One B-rep face of a CAD part: STEP entity #565.
In plain terms, the planar face has unit normal (0, -1, 0).
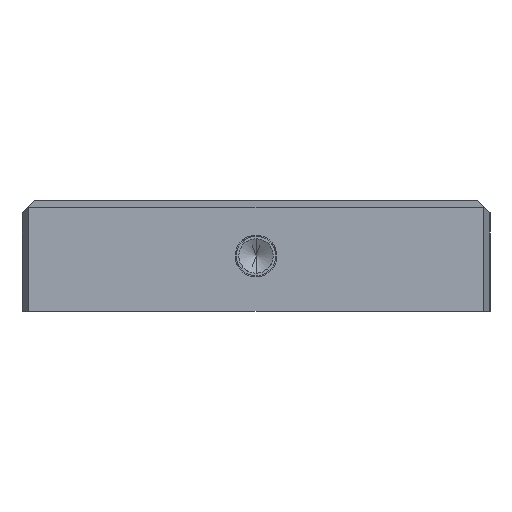
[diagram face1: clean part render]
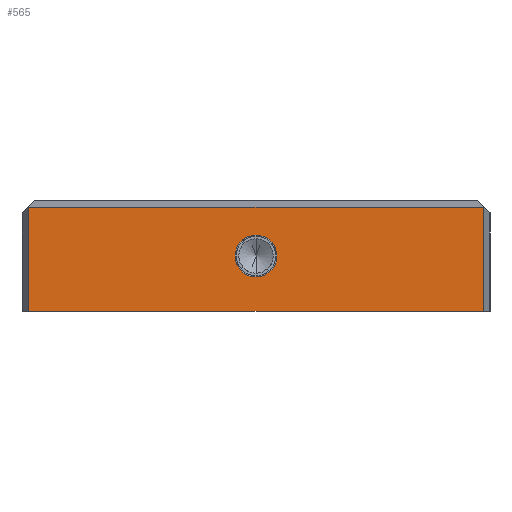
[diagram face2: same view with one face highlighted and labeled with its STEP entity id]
Its self-contained STEP definition (entity closure, numbers rounded to 3 decimals):
#457=CARTESIAN_POINT('Vertex',(0.,0.,-31.)) ;
#461=CARTESIAN_POINT('Control Point',(8.5,0.,-22.5)) ;
#462=CARTESIAN_POINT('Control Point',(8.5,0.,-25.17)) ;
#463=CARTESIAN_POINT('Control Point',(7.454,0.,-27.843)) ;
#464=CARTESIAN_POINT('Control Point',(5.343,0.,-29.954)) ;
#465=CARTESIAN_POINT('Control Point',(2.67,0.,-31.)) ;
#466=CARTESIAN_POINT('Control Point',(0.,0.,-31.)) ;
#467=CARTESIAN_POINT('Vertex',(8.5,0.,-22.5)) ;
#470=CARTESIAN_POINT('Axis2P3D Location',(0.,0.,-22.5)) ;
#474=CARTESIAN_POINT('Vertex',(0.,0.,-14.)) ;
#496=CARTESIAN_POINT('Axis2P3D Location',(0.,0.,-22.5)) ;
#500=CARTESIAN_POINT('Vertex',(-8.5,0.,-22.5)) ;
#504=CARTESIAN_POINT('Control Point',(0.,0.,-31.)) ;
#505=CARTESIAN_POINT('Control Point',(-2.67,0.,-31.)) ;
#506=CARTESIAN_POINT('Control Point',(-5.343,0.,-29.954)) ;
#507=CARTESIAN_POINT('Control Point',(-7.454,0.,-27.843)) ;
#508=CARTESIAN_POINT('Control Point',(-8.5,0.,-25.17)) ;
#509=CARTESIAN_POINT('Control Point',(-8.5,0.,-22.5)) ;
#520=CARTESIAN_POINT('Axis2P3D Location',(-92.321,0.,-45.)) ;
#525=CARTESIAN_POINT('Line Origine',(92.321,0.,-23.84)) ;
#529=CARTESIAN_POINT('Vertex',(92.321,0.,-45.)) ;
#531=CARTESIAN_POINT('Vertex',(92.321,0.,-2.679)) ;
#534=CARTESIAN_POINT('Line Origine',(0.,0.,-2.679)) ;
#538=CARTESIAN_POINT('Vertex',(-92.321,0.,-2.679)) ;
#541=CARTESIAN_POINT('Line Origine',(-92.321,0.,-23.84)) ;
#545=CARTESIAN_POINT('Vertex',(-92.321,0.,-45.)) ;
#548=CARTESIAN_POINT('Line Origine',(0.,0.,-45.)) ;
#471=DIRECTION('Axis2P3D Direction',(0.,-1.,0.)) ;
#497=DIRECTION('Axis2P3D Direction',(0.,-1.,0.)) ;
#521=DIRECTION('Axis2P3D Direction',(0.,-1.,0.)) ;
#522=DIRECTION('Axis2P3D XDirection',(0.,0.,-1.)) ;
#526=DIRECTION('Vector Direction',(0.,0.,1.)) ;
#535=DIRECTION('Vector Direction',(-1.,0.,0.)) ;
#542=DIRECTION('Vector Direction',(0.,0.,1.)) ;
#549=DIRECTION('Vector Direction',(1.,0.,0.)) ;
#472=AXIS2_PLACEMENT_3D('Circle Axis2P3D',#470,#471,$) ;
#498=AXIS2_PLACEMENT_3D('Circle Axis2P3D',#496,#497,$) ;
#523=AXIS2_PLACEMENT_3D('Plane Axis2P3D',#520,#521,#522) ;
#554=ORIENTED_EDGE('',*,*,#533,.T.) ;
#555=ORIENTED_EDGE('',*,*,#540,.T.) ;
#556=ORIENTED_EDGE('',*,*,#547,.F.) ;
#557=ORIENTED_EDGE('',*,*,#552,.T.) ;
#560=ORIENTED_EDGE('',*,*,#469,.T.) ;
#561=ORIENTED_EDGE('',*,*,#510,.T.) ;
#562=ORIENTED_EDGE('',*,*,#502,.T.) ;
#563=ORIENTED_EDGE('',*,*,#476,.T.) ;
#564=FACE_BOUND('',#559,.T.) ;
#527=VECTOR('Line Direction',#526,1.) ;
#536=VECTOR('Line Direction',#535,1.) ;
#543=VECTOR('Line Direction',#542,1.) ;
#550=VECTOR('Line Direction',#549,1.) ;
#565=ADVANCED_FACE('A927-190X315X45',(#558,#564),#524,.T.) ;
#460=B_SPLINE_CURVE_WITH_KNOTS('',5,(#461,#462,#463,#464,#465,#466),.UNSPECIFIED.,.F.,.U.,(6,6),(-6.676,6.676),.UNSPECIFIED.) ;
#503=B_SPLINE_CURVE_WITH_KNOTS('',5,(#504,#505,#506,#507,#508,#509),.UNSPECIFIED.,.F.,.U.,(6,6),(-6.676,6.676),.UNSPECIFIED.) ;
#473=CIRCLE('generated circle',#472,8.5) ;
#499=CIRCLE('generated circle',#498,8.5) ;
#469=EDGE_CURVE('',#468,#458,#460,.T.) ;
#476=EDGE_CURVE('',#475,#468,#473,.F.) ;
#502=EDGE_CURVE('',#501,#475,#499,.F.) ;
#510=EDGE_CURVE('',#458,#501,#503,.T.) ;
#533=EDGE_CURVE('',#530,#532,#528,.T.) ;
#540=EDGE_CURVE('',#532,#539,#537,.T.) ;
#547=EDGE_CURVE('',#546,#539,#544,.T.) ;
#552=EDGE_CURVE('',#546,#530,#551,.T.) ;
#553=EDGE_LOOP('',(#554,#555,#556,#557)) ;
#559=EDGE_LOOP('',(#560,#561,#562,#563)) ;
#558=FACE_OUTER_BOUND('',#553,.T.) ;
#528=LINE('Line',#525,#527) ;
#537=LINE('Line',#534,#536) ;
#544=LINE('Line',#541,#543) ;
#551=LINE('Line',#548,#550) ;
#524=PLANE('Plane',#523) ;
#458=VERTEX_POINT('',#457) ;
#468=VERTEX_POINT('',#467) ;
#475=VERTEX_POINT('',#474) ;
#501=VERTEX_POINT('',#500) ;
#530=VERTEX_POINT('',#529) ;
#532=VERTEX_POINT('',#531) ;
#539=VERTEX_POINT('',#538) ;
#546=VERTEX_POINT('',#545) ;
